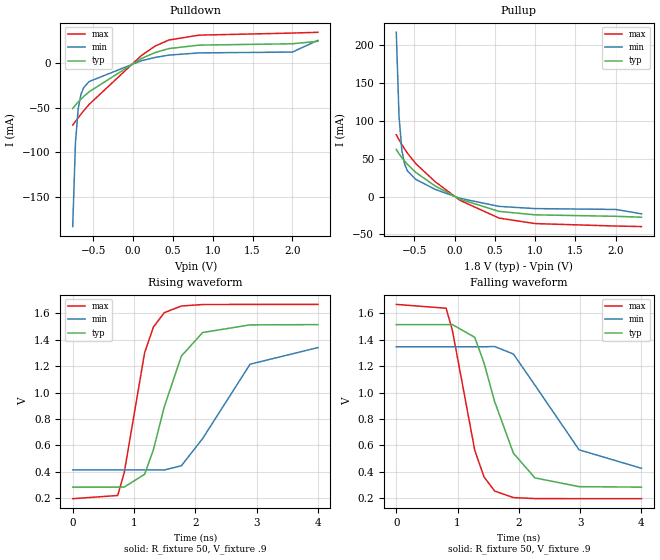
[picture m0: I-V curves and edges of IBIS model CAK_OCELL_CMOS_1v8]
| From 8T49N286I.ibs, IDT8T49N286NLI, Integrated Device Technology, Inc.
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| 3.25758e+00   -2.17526e-02   -5.28437e-01   -1.11612e-02
| 3.33333e+00   -5.02557e-02   -7.41905e-01   -2.20995e-02
| 3.40909e+00   -2.62296e-01   -9.55738e-01   -3.45860e-02
| 3.48485e+00   -5.48283e-01   -1.16984e+00   -4.61839e-02
| 3.56061e+00   -8.34620e-01   -1.38416e+00   -9.03549e-02
| 3.63636e+00   -1.12128e+00   -1.59867e+00   -4.17005e-01
| 3.71212e+00   -1.40822e+00   -1.81336e+00   -7.83863e-01
| 3.78788e+00   -1.69544e+00   -2.02823e+00   -1.15106e+00
| 3.86364e+00   -1.98290e+00   -2.24326e+00   -1.51854e+00
| 3.93939e+00   -2.27059e+00   -2.45845e+00   -1.88629e+00
| 4.01515e+00   -2.55849e+00   -2.67380e+00   -2.25425e+00
| 4.09091e+00   -2.84658e+00   -2.88929e+00   -2.62240e+00
| 4.16667e+00   -3.13483e+00   -3.10491e+00   -2.99072e+00
| 4.24242e+00   -3.42324e+00   -3.32067e+00   -3.35917e+00
| 4.31818e+00   -3.71177e+00   -3.53656e+00   -3.72774e+00
| 4.39394e+00   -4.00043e+00   -3.75256e+00   -4.09641e+00
| 4.46970e+00   -4.28920e+00   -3.96868e+00   -4.46517e+00
| 4.54545e+00   -4.57807e+00   -4.18490e+00   -4.83401e+00
| 4.62121e+00   -4.86701e+00   -4.40122e+00   -5.20293e+00
| 4.69697e+00   -5.15604e+00   -4.61763e+00   -5.57191e+00
| 4.77273e+00   -5.44513e+00   -4.83413e+00   -5.94093e+00
| 4.84848e+00   -5.73428e+00   -5.05072e+00   -6.31000e+00
| 4.92424e+00   -6.02348e+00   -5.26738e+00   -6.67909e+00
| 5.00000e+00   -6.31272e+00   -5.48412e+00   -7.04821e+00
[Model]   CAK_OCELL_CMOS_1v8
Model_type   Output
Polarity   Non-Inverting
|   typ   min   max
C_comp   2pF   1.5pF   2.5pF
Vmeas = .9
Rref = 50
Cref = 0
Vref = .9
|   typ   min   max
[Voltage range]   1.8V   1.710V   1.890V
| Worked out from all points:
|   slope of the pulldown table from 0 to 0.27 V, typ, clamps not added: 22.7 ohm
|   slope of the pullup table from 0 to 0.27 V, typ, clamps not added: 22.9 ohm
|   rising waveform, R_fixture 50, V_fixture .9: 20-80 % time 472ps typ, 713ps min, 340ps max; typ from 0.284 V to 1.51 V
|   falling waveform, R_fixture 50, V_fixture .9: 20-80 % time 521ps typ, 753ps min, 370ps max; typ from 1.51 V to 0.284 V
[Pulldown]
|Voltage   I (typ)   I (min)   I (max)
|Note, modeling breaks down at 250mA and above.  This is well beyond the functional   |
|operating range of the device.  Should this scenario occur, catastrophic failure and   |
|possible damage to the device and/or board is of higher concern than the I-V curve   |
|behavior.  The IBIS checker will flag currents in excess of 10A with warnings.  Lines   |
|with currents in excess of 0.35 A have been commented out.  The points still remain|
|available to the user if the user desires to use them.   |
|-1.64000e+00   -8.45060e+00   -7.45572e+00   -9.66339e+00
|-1.48000e+00   -6.67178e+00   -6.12326e+00   -7.39014e+00
|-1.32000e+00   -4.89321e+00   -4.79099e+00   -5.11762e+00
|-1.16000e+00   -3.11502e+00   -3.45890e+00   -2.84539e+00
|-1.00000e+00   -1.33737e+00   -2.12700e+00   -5.73190e-01
|-9.99000e-01   -1.32626e+00   -2.11868e+00   -5.58990e-01
|-9.64529e-01   -9.43359e-01   -1.83177e+00   -1.98497e-01
|-9.30057e-01   -5.60487e-01   -1.54487e+00   -1.08372e-01
|-8.95586e-01   -2.31853e-01   -1.25801e+00   -8.77808e-02
|-8.61115e-01   -1.06256e-01   -9.71177e-01   -8.09581e-02
|-8.26644e-01   -6.89430e-02   -6.84381e-01   -7.68578e-02
|-7.92172e-01   -5.64352e-02   -4.00585e-01   -7.32011e-02
-757.7mV  -50.72mA   -183.3mA   -69.36mA
-723.2mV  -46.79mA   -89.01mA   -65.29mA
-688.8mV  -43.4mA    -50.99mA   -61.16mA
-654.3mV  -40.24mA   -34.84mA   -57.11mA
-619.8mV  -37.28mA   -27.27mA   -53.21mA
-550.9mV  -31.9mA    -20.42mA   -46.04mA
104.1mV   5.354mA    2.89mA     8.71mA
276.4mV   12.09mA    6.64mA     19.38mA
448.8mV   16.55mA    9.236mA    26.18mA
828mV     20.45mA    11.72mA    31.67mA
2.001V    21.99mA    12.65mA    33.99mA
2.321V    24.71mA    25.86mA    34.86mA
| 2.64060e+00   1.12686e-01   2.85444e+00   5.71416e-02
| 2.96040e+00   5.51975e+00   7.41138e+00   2.84717e+00
| 3.28020e+00   1.16082e+01   1.19723e+01   1.06308e+01
| 3.60000e+00   1.77021e+01   1.65374e+01   1.84207e+01
[Pullup]
|Voltage   I (typ)   I (min)   I (max)
|Note, modeling breaks down at 250mA and above.  This is well beyond the functional   |
|operating range of the device.  Should this scenario occur, catastrophic failure and   |
|possible damage to the device and/or board is of higher concern than the I-V curve   |
|behavior.  The IBIS checker will flag currents in excess of 10A with warnings.  Lines   |
|with currents in excess of 0.35 A have been commented out.  The points still remain|
|available to the user if the user desires to use them.   |
|-1.64000e+00   1.47162e+01   1.30180e+01   1.67914e+01
|-1.48000e+00   1.16627e+01   1.07308e+01   1.28878e+01
|-1.32000e+00   8.61028e+00   8.44452e+00   8.98520e+00
|-1.16000e+00   5.55874e+00   6.15894e+00   5.08347e+00
|-1.00000e+00   2.50796e+00   3.87398e+00   1.18251e+00
|-9.99000e-01   2.48890e+00   3.85970e+00   1.15813e+00
|-9.64529e-01   1.83169e+00   3.36748e+00   4.46554e-01
|-9.30057e-01   1.17449e+00   2.87526e+00   1.79719e-01
|-8.95586e-01   5.69042e-01   2.38303e+00   1.24495e-01
|-8.61115e-01   2.24186e-01   1.89075e+00   1.09758e-01
|-8.26644e-01   1.16045e-01   1.39834e+00   1.02419e-01
|-7.92172e-01   8.31335e-02   9.07732e-01   9.59623e-02
|-7.57701e-01   7.01040e-02   4.82756e-01   8.90038e-02
-723.2mV  62.45mA    217.4mA    81.87mA
-688.8mV  56.59mA    105.8mA    75.11mA
-654.3mV  51.54mA    61.61mA    68.83mA
-619.8mV  46.97mA    42.97mA    63.02mA
-585.3mV  42.79mA    34.1mA     57.63mA
-481.9mV  32.08mA    22.8mA     43.7mA
-240.6mV  14.08mA    9.573mA    19.72mA
69.61mV   -3.487mA   -2.304mA   -5.032mA
552.2mV   -19.55mA   -12.95mA   -28.42mA
1V        -24.13mA   -15.87mA   -35.71mA
2.001V    -26.07mA   -16.99mA   -38.95mA
2.321V    -27.3mA    -22.8mA    -39.65mA
| 2.64060e+00   -6.63615e-02   -1.53996e+00   -5.63223e-02
| 2.96040e+00   -3.10270e+00   -4.19870e+00   -1.55653e+00
| 3.28020e+00   -6.65517e+00   -6.85936e+00   -6.09630e+00
| 3.60000e+00   -1.02097e+01   -9.52145e+00   -1.06396e+01
[Ramp]
|   typ   min   max
dV/dt_r   0.74/0.473n   0.557/0.715n   0.883/0.339n
dV/dt_f   0.74/0.521n   0.553/0.755n   0.884/0.37n
R_load =   50.0000
[Rising Waveform]
R_fixture = 50
V_fixture = .9   |Vcc_typ
V_fixture_min = .855 |Vcc_min
V_fixture_max = .945 |Vcc_max
C_fixture = 0.0p
| Time   typ   min   max
0s        283.8mV    414.7mV    196.6mV
733.3ps   283.9mV    414.7mV    220.5mV
840ps     284mV      414.7mV    392.7mV
1.173ns   381.4mV    414.7mV    1.302V
1.316ns   567mV      414.9mV    1.496V
1.493ns   891.3mV    413.5mV    1.605V
1.773ns   1.277V     446.1mV    1.656V
2.12ns    1.455V     652.3mV    1.667V
2.893ns   1.513V     1.215V     1.668V
4ns       1.515V     1.341V     1.668V
[Falling Waveform]
R_fixture = 50
V_fixture = .9   |Vcc_typ
V_fixture_min = .855 |Vcc_min
V_fixture_max = .945 |Vcc_max
C_fixture = 0.0p
| Time   typ   min   max
0s        1.515V     1.347V     1.668V
813.3ps   1.515V     1.347V     1.639V
915.6ps   1.515V     1.347V     1.471V
1.28ns    1.419V     1.347V     563.3mV
1.431ns   1.225V     1.347V     361.5mV
1.604ns   932.5mV    1.349V     254.7mV
1.911ns   540.9mV    1.292V     204.7mV
2.262ns   353.9mV    1.056V     197.4mV
2.982ns   287.7mV    566.7mV    196.6mV
4ns       283.9mV    426.6mV    196.6mV
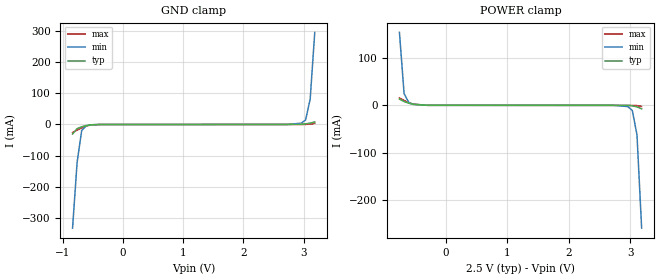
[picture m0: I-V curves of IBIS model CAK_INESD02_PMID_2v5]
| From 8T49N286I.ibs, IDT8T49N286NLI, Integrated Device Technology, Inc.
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| 3.25758e+00   -1.32932e-02   -4.69388e-01   -6.85289e-03
| 3.33333e+00   -3.04767e-02   -6.80964e-01   -1.35047e-02
| 3.40909e+00   -1.97405e-01   -8.92761e-01   -2.10928e-02
| 3.48485e+00   -4.80463e-01   -1.10472e+00   -2.81524e-02
| 3.56061e+00   -7.63732e-01   -1.31681e+00   -5.47589e-02
| 3.63636e+00   -1.04719e+00   -1.52902e+00   -3.40294e-01
| 3.71212e+00   -1.33083e+00   -1.74134e+00   -7.02945e-01
| 3.78788e+00   -1.61464e+00   -1.95377e+00   -1.06580e+00
| 3.86364e+00   -1.89859e+00   -2.16629e+00   -1.42883e+00
| 3.93939e+00   -2.18269e+00   -2.37891e+00   -1.79201e+00
| 4.01515e+00   -2.46691e+00   -2.59162e+00   -2.15533e+00
| 4.09091e+00   -2.75125e+00   -2.80442e+00   -2.51876e+00
| 4.16667e+00   -3.03569e+00   -3.01730e+00   -2.88228e+00
| 4.24242e+00   -3.32022e+00   -3.23027e+00   -3.24589e+00
| 4.31818e+00   -3.60483e+00   -3.44330e+00   -3.60956e+00
| 4.39394e+00   -3.88952e+00   -3.65641e+00   -3.97330e+00
| 4.46970e+00   -4.17427e+00   -3.86959e+00   -4.33710e+00
| 4.54545e+00   -4.45909e+00   -4.08283e+00   -4.70095e+00
| 4.62121e+00   -4.74395e+00   -4.29613e+00   -5.06484e+00
| 4.69697e+00   -5.02886e+00   -4.50948e+00   -5.42878e+00
| 4.77273e+00   -5.31381e+00   -4.72289e+00   -5.79275e+00
| 4.84848e+00   -5.59879e+00   -4.93635e+00   -6.15675e+00
| 4.92424e+00   -5.88381e+00   -5.14986e+00   -6.52077e+00
| 5.00000e+00   -6.16885e+00   -5.36341e+00   -6.88480e+00
[Model] CAK_INESD02_PMID_2v5
Model_type   Input
Polarity   Non-Inverting
Vinl = 0.7V
Vinh = 1.7V
|   typ   min   max
C_comp   2pF   1.5pF   2.5pF
|   typ   min   max
[Voltage range]   2.5V   2.375V   2.625V
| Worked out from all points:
|   GND clamp passes 1 mA (typ) near -0.53 V on its own axis
|   POWER clamp passes 1 mA (typ) near -0.48 V on its own axis
[GND_clamp]
|Voltage   I (typ)   I (min)   I (max)
|Note, modeling breaks down at 250mA and above.  This is well beyond the functional   |
|operating range of the device.  Should this scenario occur, catastrophic failure and   |
|possible damage to the device and/or board is of higher concern than the I-V curve   |
|behavior.  The IBIS checker will flag currents in excess of 10A with warnings.  Lines   |
|with currents in excess of 0.35 A have been commented out.  The points still remain|
|available to the user if the user desires to use them.   |
|-2.50000e+00   -6.16895e+00   -5.01116e+00   -7.48559e+00
|-2.42424e+00   -5.88390e+00   -4.79768e+00   -7.12154e+00
|-2.34848e+00   -5.59889e+00   -4.58425e+00   -6.75750e+00
|-2.27273e+00   -5.31390e+00   -4.37088e+00   -6.39347e+00
|-2.19697e+00   -5.02895e+00   -4.15756e+00   -6.02946e+00
|-2.12121e+00   -4.74404e+00   -3.94430e+00   -5.66547e+00
|-2.04545e+00   -4.45918e+00   -3.73109e+00   -5.30151e+00
|-1.96970e+00   -4.17436e+00   -3.51796e+00   -4.93758e+00
|-1.89394e+00   -3.88961e+00   -3.30490e+00   -4.57370e+00
|-1.81818e+00   -3.60492e+00   -3.09191e+00   -4.20986e+00
|-1.74242e+00   -3.32030e+00   -2.87899e+00   -3.84609e+00
|-1.66667e+00   -3.03577e+00   -2.66616e+00   -3.48237e+00
|-1.59091e+00   -2.75133e+00   -2.45342e+00   -3.11872e+00
|-1.51515e+00   -2.46699e+00   -2.24077e+00   -2.75514e+00
|-1.43939e+00   -2.18277e+00   -2.02821e+00   -2.39164e+00
|-1.36364e+00   -1.89867e+00   -1.81575e+00   -2.02825e+00
|-1.28788e+00   -1.61471e+00   -1.60339e+00   -1.66497e+00
|-1.21212e+00   -1.33091e+00   -1.39114e+00   -1.30184e+00
|-1.13636e+00   -1.04727e+00   -1.17900e+00   -9.38864e-01
|-1.06061e+00   -7.63803e-01   -9.66990e-01   -5.76078e-01
|-9.84848e-01   -4.80532e-01   -7.55130e-01   -2.13501e-01
|-9.09091e-01   -1.97473e-01   -5.43466e-01   -3.76738e-02
-833.3mV  -30.54mA   -332.1mA   -25.65mA
-757.6mV  -13.36mA   -120.7mA   -18.55mA
-681.8mV  -7.383mA   -19.06mA   -11.06mA
-606.1mV  -3.294mA   -4.129mA   -5.066mA
-530.3mV  -997.9uA   -1.06mA    -1.479mA
-378.8mV  -81.26uA   -88.94uA   -93.18uA
2.727V    59.1uA     121uA      65.12uA
2.955V    596.4uA    4.136mA    85.43uA
3.03V     1.982mA    14.16mA    231.7uA
3.106V    4.438mA    81.6mA     1.173mA
3.182V    7.992mA    295.1mA    3.436mA
| 3.25758e+00   1.31680e-02   5.12428e-01   7.02139e-03
| 3.33333e+00   3.25724e-02   7.29725e-01   1.18654e-02
| 3.40909e+00   2.27266e-01   9.47135e-01   1.72034e-02
| 3.48485e+00   5.17409e-01   1.16468e+00   2.19847e-02
| 3.56061e+00   8.07728e-01   1.38237e+00   5.23158e-02
| 3.63636e+00   1.09824e+00   1.60020e+00   3.65997e-01
| 3.71212e+00   1.38894e+00   1.81817e+00   7.37335e-01
| 3.78788e+00   1.67983e+00   2.03629e+00   1.10891e+00
| 3.86364e+00   1.97091e+00   2.25454e+00   1.48073e+00
| 3.93939e+00   2.26217e+00   2.47294e+00   1.85278e+00
| 4.01515e+00   2.55361e+00   2.69148e+00   2.22506e+00
| 4.09091e+00   2.84523e+00   2.91016e+00   2.59755e+00
| 4.16667e+00   3.13703e+00   3.12898e+00   2.97026e+00
| 4.24242e+00   3.42899e+00   3.34794e+00   3.34317e+00
| 4.31818e+00   3.72112e+00   3.56704e+00   3.71628e+00
| 4.39394e+00   4.01342e+00   3.78629e+00   4.08959e+00
| 4.46970e+00   4.30588e+00   4.00567e+00   4.46308e+00
| 4.54545e+00   4.59850e+00   4.22520e+00   4.83676e+00
| 4.62121e+00   4.89128e+00   4.44488e+00   5.21061e+00
| 4.69697e+00   5.18421e+00   4.66471e+00   5.58464e+00
| 4.77273e+00   5.47731e+00   4.88468e+00   5.95883e+00
| 4.84848e+00   5.77057e+00   5.10481e+00   6.33320e+00
| 4.92424e+00   6.06399e+00   5.32510e+00   6.70773e+00
| 5.00000e+00   6.35756e+00   5.54554e+00   7.08242e+00
[Power_clamp]
|Voltage   I (typ)   I (min)   I (max)
|Note, modeling breaks down at 250mA and above.  This is well beyond the functional   |
|operating range of the device.  Should this scenario occur, catastrophic failure and   |
|possible damage to the device and/or board is of higher concern than the I-V curve   |
|behavior.  The IBIS checker will flag currents in excess of 10A with warnings.  Lines   |
|with currents in excess of 0.35 A have been commented out.  The points still remain|
|available to the user if the user desires to use them.   |
|-2.50000e+00   6.35756e+00   5.18189e+00   7.70102e+00
|-2.42424e+00   6.06399e+00   4.96171e+00   7.32606e+00
|-2.34848e+00   5.77057e+00   4.74168e+00   6.95126e+00
|-2.27273e+00   5.47731e+00   4.52180e+00   6.57663e+00
|-2.19697e+00   5.18421e+00   4.30207e+00   6.20215e+00
|-2.12121e+00   4.89128e+00   4.08249e+00   5.82785e+00
|-2.04545e+00   4.59850e+00   3.86306e+00   5.45371e+00
|-1.96970e+00   4.30588e+00   3.64376e+00   5.07974e+00
|-1.89394e+00   4.01342e+00   3.42461e+00   4.70595e+00
|-1.81818e+00   3.72112e+00   3.20560e+00   4.33234e+00
|-1.74242e+00   3.42899e+00   2.98673e+00   3.95891e+00
|-1.66667e+00   3.13703e+00   2.76800e+00   3.58567e+00
|-1.59091e+00   2.84523e+00   2.54941e+00   3.21263e+00
|-1.51515e+00   2.55361e+00   2.33097e+00   2.83979e+00
|-1.43939e+00   2.26217e+00   2.11266e+00   2.46715e+00
|-1.36364e+00   1.97091e+00   1.89450e+00   2.09473e+00
|-1.28788e+00   1.67983e+00   1.67647e+00   1.72254e+00
|-1.21212e+00   1.38894e+00   1.45859e+00   1.35057e+00
|-1.13636e+00   1.09824e+00   1.24086e+00   9.78833e-01
|-1.06061e+00   8.07728e-01   1.02326e+00   6.07339e-01
|-9.84848e-01   5.17409e-01   8.05803e-01   2.36085e-01
|-9.09091e-01   2.27266e-01   5.88473e-01   3.12941e-02
|-8.33333e-01   3.25724e-02   3.71194e-01   2.01370e-02
-757.6mV  13.17mA    153.4mA    15.42mA
-681.8mV  7.992mA    24.73mA    10.04mA
-606.1mV  4.438mA    6.043mA    5.618mA
-530.3mV  1.982mA    2.167mA    2.491mA
-303mV    67.49uA    68.92uA    77.83uA
2.727V    -58.92uA   -71.21uA   -65.12uA
2.955V    -222.7uA   -2.559mA   -77.6uA
3.03V     -997.9uA   -10.75mA   -119.7uA
3.106V    -3.295mA   -61.69mA   -506.7uA
3.182V    -7.383mA   -258.2mA   -2.426mA
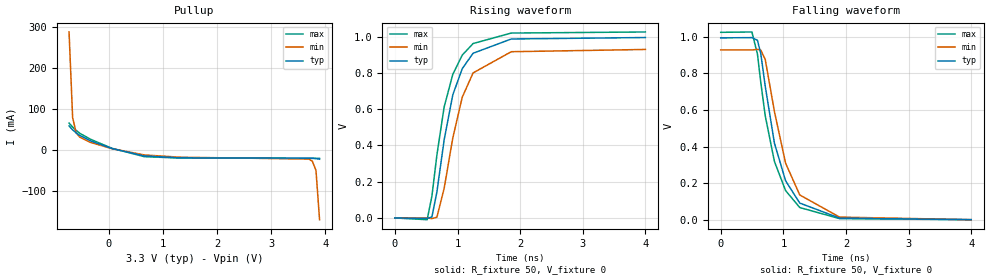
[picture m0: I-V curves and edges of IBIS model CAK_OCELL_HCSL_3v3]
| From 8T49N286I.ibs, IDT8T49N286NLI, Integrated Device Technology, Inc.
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| 3.25758e+00   -2.17677e-02   -5.28452e-01   -1.11757e-02
| 3.33333e+00   -5.02723e-02   -7.41922e-01   -2.21158e-02
| 3.40909e+00   -2.62314e-01   -9.55756e-01   -3.46040e-02
| 3.48485e+00   -5.48303e-01   -1.16986e+00   -4.62037e-02
| 3.56061e+00   -8.34641e-01   -1.38418e+00   -9.03765e-02
| 3.63636e+00   -1.12130e+00   -1.59869e+00   -4.17028e-01
| 3.71212e+00   -1.40825e+00   -1.81339e+00   -7.83888e-01
| 3.78788e+00   -1.69546e+00   -2.02826e+00   -1.15108e+00
| 3.86364e+00   -1.98293e+00   -2.24329e+00   -1.51857e+00
| 3.93939e+00   -2.27062e+00   -2.45848e+00   -1.88632e+00
| 4.01515e+00   -2.55852e+00   -2.67383e+00   -2.25428e+00
| 4.09091e+00   -2.84661e+00   -2.88932e+00   -2.62244e+00
| 4.16667e+00   -3.13486e+00   -3.10494e+00   -2.99075e+00
| 4.24242e+00   -3.42327e+00   -3.32071e+00   -3.35921e+00
| 4.31818e+00   -3.71181e+00   -3.53659e+00   -3.72777e+00
| 4.39394e+00   -4.00047e+00   -3.75260e+00   -4.09645e+00
| 4.46970e+00   -4.28924e+00   -3.96871e+00   -4.46521e+00
| 4.54545e+00   -4.57811e+00   -4.18494e+00   -4.83406e+00
| 4.62121e+00   -4.86706e+00   -4.40126e+00   -5.20297e+00
| 4.69697e+00   -5.15608e+00   -4.61767e+00   -5.57195e+00
| 4.77273e+00   -5.44517e+00   -4.83417e+00   -5.94098e+00
| 4.84848e+00   -5.73432e+00   -5.05076e+00   -6.31005e+00
| 4.92424e+00   -6.02353e+00   -5.26742e+00   -6.67914e+00
| 5.00000e+00   -6.31277e+00   -5.48416e+00   -7.04826e+00
[Model]   CAK_OCELL_HCSL_3v3
Model_type   Open_source
Polarity   Non-Inverting
|   typ   min   max
C_comp   2pF   1.5pF   2.5pF
Vmeas = 0.493V
Rref = 50
Cref = 0
Vref = 0V
|   typ   min   max
[Voltage range]   3.3V   3.135V   3.465V
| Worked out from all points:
|   slope of the pullup table from 0 to 0.495 V, typ, clamps not added: 28.9 ohm
|   rising waveform, R_fixture 50, V_fixture 0: 20-80 % time 344ps typ, 361ps min, 335ps max; typ from 0 V to 0.994 V
|   falling waveform, R_fixture 50, V_fixture 0: 20-80 % time 367ps typ, 387ps min, 354ps max; typ from 0.995 V to 0 V
[Pullup]
|Voltage   I (typ)   I (min)   I (max)
|Note, modeling breaks down at 250mA and above.  This is well beyond the functional   |
|operating range of the device.  Should this scenario occur, catastrophic failure and   |
|possible damage to the device and/or board is of higher concern than the I-V curve   |
|behavior.  The IBIS checker will flag currents in excess of 10A with warnings.  Lines   |
|with currents in excess of 0.35 A have been commented out.  The points still remain|
|available to the user if the user desires to use them.   |
|-2.84000e+00   3.76337e+01   3.02266e+01   4.60386e+01
|-2.38000e+00   2.88353e+01   2.36271e+01   3.48025e+01
|-1.92000e+00   2.00455e+01   1.70341e+01   2.35778e+01
|-1.46000e+00   1.12666e+01   1.04494e+01   1.23613e+01
|-1.00000e+00   2.49686e+00   3.87575e+00   1.15381e+00
|-9.99000e-01   2.47780e+00   3.86147e+00   1.12946e+00
|-9.32920e-01   1.21878e+00   2.91795e+00   1.62522e-01
|-8.66839e-01   2.50070e-01   1.97451e+00   8.66814e-02
|-8.00759e-01   8.04803e-02   1.03083e+00   7.55811e-02
-734.7mV  58.68mA    288.2mA    65.68mA
-668.6mV  49.14mA    78.97mA    56.05mA
-602.5mV  41.69mA    41.59mA    47.75mA
-536.4mV  35.41mA    31.29mA    40.77mA
-338.2mV  22.15mA    18.41mA    26.11mA
58.29mV   3.471mA    3.133mA    4mA
653mV     -14.6mA    -12.15mA   -16.36mA
1.314V    -19.22mA   -17.74mA   -19.81mA
3.693V    -20mA      -22.15mA   -20.55mA
3.759V    -20.18mA   -27.74mA   -20.55mA
3.825V    -20.9mA    -49.97mA   -20.56mA
3.891V    -22.63mA   -170.3mA   -20.57mA
| 3.95703e+00   -2.55106e-02   -6.35182e-01   -2.07095e-02
| 4.02311e+00   -2.96327e-02   -1.18457e+00   -2.14473e-02
| 4.08920e+00   -3.70823e-02   -1.73419e+00   -2.35577e-02
| 4.15528e+00   -7.66055e-02   -2.28400e+00   -2.72241e-02
| 4.22136e+00   -4.43600e-01   -2.83393e+00   -3.21110e-02
| 4.28744e+00   -1.17580e+00   -3.38397e+00   -3.73207e-02
| 4.35352e+00   -1.90900e+00   -3.93410e+00   -4.49688e-02
| 4.41960e+00   -2.64245e+00   -4.48431e+00   -1.14488e-01
| 4.48568e+00   -3.37611e+00   -5.03461e+00   -8.22366e-01
| 4.55176e+00   -4.10995e+00   -5.58498e+00   -1.75907e+00
| 4.61784e+00   -4.84392e+00   -6.13542e+00   -2.69589e+00
| 4.68392e+00   -5.57800e+00   -6.68593e+00   -3.63296e+00
| 4.75000e+00   -6.31219e+00   -7.23650e+00   -4.57036e+00
| 4.75100e+00   -6.32330e+00   -7.24483e+00   -4.58454e+00
| 5.12080e+00   -1.04334e+01   -1.03270e+01   -9.83365e+00
| 5.49060e+00   -1.45450e+01   -1.34107e+01   -1.50850e+01
| 5.86040e+00   -1.86577e+01   -1.64956e+01   -2.03373e+01
| 6.23020e+00   -2.27711e+01   -1.95815e+01   -2.55902e+01
| 6.60000e+00   -2.68852e+01   -2.26683e+01   -3.08435e+01
[Ramp]
|   typ   min   max
dV/dt_r   0.603/0.344n   0.562/0.362n   0.622/0.335n
dV/dt_f   0.598/0.367n   0.559/0.387n   0.617/0.354n
R_load =   50.0000
[Rising Waveform]
R_fixture = 50
V_fixture = 0   | VCC_typ
V_fixture_max = 0   | VCC_max
V_fixture_min = 0   | VCC_min
C_fixture = 0.0p
| Time   typ   min   max
0s        23.76nV    382.4nV    37.47nV
515.6ps   -3.231mV   8.69uV     -9.537mV
591.1ps   5.737mV    -3.519mV   120mV
671.1ps   144mV      4.007mV    347.5mV
786.7ps   430.5mV    163mV      611.6mV
924.4ps   678.2mV    440.3mV    791.1mV
1.076ns   823.1mV    665.7mV    897.6mV
1.249ns   907.8mV    799.5mV    961.3mV
1.858ns   986.3mV    916.2mV    1.019V
4ns       994.4mV    928.6mV    1.025V
[Falling Waveform]
R_fixture = 50
V_fixture = 0   | VCC_typ
V_fixture_max = 0   | VCC_max
V_fixture_min = 0   | VCC_min
C_fixture = 0.0p
| Time   typ   min   max
0s        994.6mV    928.7mV    1.025V
497.8ps   996.1mV    928.5mV    1.027V
586.7ps   981.8mV    931.8mV    906mV
640ps     907.5mV    927.3mV    750.4mV
711.1ps   730mV      876.6mV    567.5mV
857.8ps   418.4mV    591.3mV    318.4mV
1.036ns   212.8mV    308.9mV    159.1mV
1.262ns   90.9mV     135.3mV    66.39mV
1.898ns   8.67mV     14.1mV     5.868mV
4ns       3.804uV    9.356uV    1.976uV
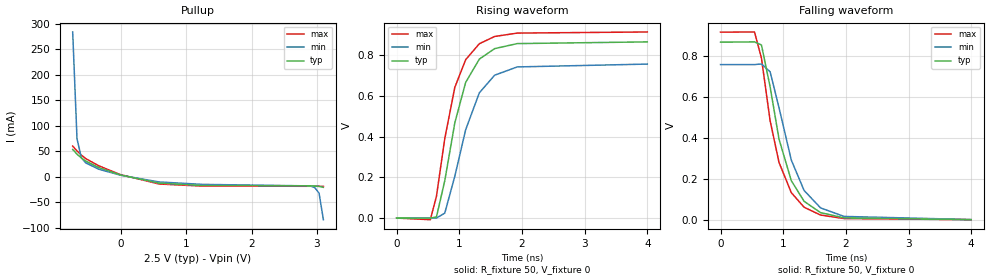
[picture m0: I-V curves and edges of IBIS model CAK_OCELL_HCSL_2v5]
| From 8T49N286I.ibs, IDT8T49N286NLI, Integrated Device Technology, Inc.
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[Model]   CAK_OCELL_HCSL_2v5
Model_type   Open_source
Polarity   Non-Inverting
|   typ   min   max
C_comp   2pF   1.5pF   2.5pF
Vmeas =0.433V
Rref = 50
Cref = 0
Vref = 0V
|   typ   min   max
[Voltage range]   2.5V   2.375V   2.625V
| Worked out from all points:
|   slope of the pullup table from 0 to 0.375 V, typ, clamps not added: 32.2 ohm
|   rising waveform, R_fixture 50, V_fixture 0: 20-80 % time 374ps typ, 413ps min, 354ps max; typ from 0 V to 0.865 V
|   falling waveform, R_fixture 50, V_fixture 0: 20-80 % time 386ps typ, 423ps min, 365ps max; typ from 0.866 V to 0 V
[Pullup]
|Voltage   I (typ)   I (min)   I (max)
|Note, modeling breaks down at 250mA and above.  This is well beyond the functional   |
|operating range of the device.  Should this scenario occur, catastrophic failure and   |
|possible damage to the device and/or board is of higher concern than the I-V curve   |
|behavior.  The IBIS checker will flag currents in excess of 10A with warnings.  Lines   |
|with currents in excess of 0.35 A have been commented out.  The points still remain|
|available to the user if the user desires to use them.   |
|-2.20000e+00   2.53860e+01   2.10376e+01   3.04001e+01
|-1.90000e+00   1.96558e+01   1.67400e+01   2.30814e+01
|-1.60000e+00   1.39304e+01   1.24459e+01   1.57666e+01
|-1.30000e+00   8.20889e+00   8.15606e+00   8.45509e+00
|-1.00000e+00   2.49130e+00   3.87082e+00   1.14775e+00
|-9.99000e-01   2.47225e+00   3.85655e+00   1.12340e+00
|-9.32920e-01   1.21338e+00   2.91317e+00   1.56613e-01
|-8.66839e-01   2.44834e-01   1.96989e+00   8.09316e-02
|-8.00759e-01   7.54247e-02   1.02638e+00   7.00161e-02
-734.7mV  53.81mA    283.9mA    60.31mA
-668.6mV  44.43mA    74.85mA    50.84mA
-602.5mV  37.13mA    37.61mA    42.69mA
-536.4mV  31.02mA    27.47mA    35.88mA
-338.2mV  18.38mA    15.14mA    21.85mA
-7.793mV  3.897mA    3.373mA    4.581mA
586.9mV   -12.2mA    -9.962mA   -13.97mA
1.248V    -16.94mA   -14.7mA    -18.04mA
2.9V      -17.59mA   -17.68mA   -18.4mA
2.966V    -17.81mA   -21.06mA   -18.4mA
3.032V    -18.62mA   -31.87mA   -18.41mA
3.098V    -20.48mA   -83.85mA   -18.49mA
| 3.16407e+00   -2.34898e-02   -3.71496e-01   -1.89730e-02
| 3.23015e+00   -2.77827e-02   -9.15597e-01   -2.06346e-02
| 3.29623e+00   -3.61539e-02   -1.46512e+00   -2.38683e-02
| 3.36231e+00   -8.61235e-02   -2.01485e+00   -2.84694e-02
| 3.42839e+00   -5.18480e-01   -2.56473e+00   -3.36823e-02
| 3.49447e+00   -1.25146e+00   -3.11472e+00   -3.96612e-02
| 3.56055e+00   -1.98469e+00   -3.66482e+00   -7.08768e-02
| 3.62663e+00   -2.71817e+00   -4.21500e+00   -5.50254e-01
| 3.69271e+00   -3.45186e+00   -4.76526e+00   -1.48693e+00
| 3.75879e+00   -4.18571e+00   -5.31560e+00   -2.42371e+00
| 3.82487e+00   -4.91970e+00   -5.86601e+00   -3.36070e+00
| 3.89095e+00   -5.65380e+00   -6.41649e+00   -4.29801e+00
| 3.95703e+00   -6.38800e+00   -6.96704e+00   -5.23558e+00
| 4.02311e+00   -7.12229e+00   -7.51765e+00   -6.17337e+00
| 4.08920e+00   -7.85665e+00   -8.06832e+00   -7.11131e+00
| 4.15528e+00   -8.59108e+00   -8.61905e+00   -8.04937e+00
| 4.22136e+00   -9.32557e+00   -9.16983e+00   -8.98752e+00
| 4.28744e+00   -1.00601e+01   -9.72066e+00   -9.92574e+00
| 4.35352e+00   -1.07947e+01   -1.02715e+01   -1.08640e+01
| 4.41960e+00   -1.15294e+01   -1.08225e+01   -1.18023e+01
| 4.48568e+00   -1.22641e+01   -1.13734e+01   -1.27407e+01
| 4.55176e+00   -1.29988e+01   -1.19245e+01   -1.36791e+01
| 4.61784e+00   -1.37336e+01   -1.24755e+01   -1.46176e+01
| 4.68392e+00   -1.44684e+01   -1.30266e+01   -1.55560e+01
| 4.75000e+00   -1.52032e+01   -1.35778e+01   -1.64945e+01
| 4.75100e+00   -1.52143e+01   -1.35861e+01   -1.65087e+01
| 4.80080e+00   -1.57681e+01   -1.40015e+01   -1.72160e+01
| 4.85060e+00   -1.63219e+01   -1.44169e+01   -1.79233e+01
| 4.90040e+00   -1.68758e+01   -1.48323e+01   -1.86307e+01
| 4.95020e+00   -1.74296e+01   -1.52477e+01   -1.93380e+01
| 5.00000e+00   -1.79835e+01   -1.56632e+01   -2.00453e+01
[Ramp]
|   typ   min   max
dV/dt_r   0.523/0.375n   0.456/0.414n   0.553/0.355n
dV/dt_f   0.521/0.386n   0.455/0.423n   0.55/0.365n
R_load =   50.0000
[Rising Waveform]
R_fixture = 50
V_fixture = 0   | VCC_typ
V_fixture_max = 0   | VCC_max
V_fixture_min = 0   | VCC_min
C_fixture = 0.0p
| Time   typ   min   max
0s        18.75uV    592uV      12.45nV
537.8ps   -65.32uV   600.7uV    -8.005mV
635.6ps   4.972mV    -100.9uV   106.4mV
768.9ps   183.7mV    24.38mV    390.8mV
928.9ps   467.8mV    205.3mV    642.1mV
1.102ns   666.4mV    434mV      777.9mV
1.32ns    780.6mV    615mV      856.1mV
1.564ns   832.1mV    701.5mV    891.7mV
1.924ns   856.8mV    742.2mV    908.4mV
4ns       865.2mV    756.2mV    913.9mV
[Falling Waveform]
R_fixture = 50
V_fixture = 0   | VCC_typ
V_fixture_max = 0   | VCC_max
V_fixture_min = 0   | VCC_min
C_fixture = 0.0p
| Time   typ   min   max
0s        865.6mV    756.3mV    914.4mV
542.2ps   866.9mV    756.2mV    915.3mV
653.3ps   851.9mV    759.4mV    787.5mV
791.1ps   648.2mV    721.5mV    483.1mV
933.3ps   393mV      546mV      279.2mV
1.129ns   190.5mV    291.1mV    132mV
1.333ns   89.73mV    142.8mV    60.79mV
1.596ns   34.43mV    57.39mV    22.61mV
1.973ns   8.737mV    15.87mV    5.467mV
4ns       24.13uV    604.1uV    2.69uV
